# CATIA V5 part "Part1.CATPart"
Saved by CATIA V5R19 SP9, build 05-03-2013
Part number: Part1
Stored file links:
  C:\Users\herve.bezard\Downloads\etiquette Soline\Part1.CATPart

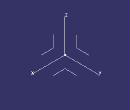
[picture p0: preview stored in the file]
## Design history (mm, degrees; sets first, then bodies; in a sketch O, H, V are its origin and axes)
AxisSystem1: origin (0, 0, 0), X (1, 0, 0), Y (0, 1, 0), Z (0, 0, 1)
Body1 (main body)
